VERSION 5.7 ;
  NOWIREEXTENSIONATPIN ON ;
  DIVIDERCHAR "/" ;
  BUSBITCHARS "[]" ;
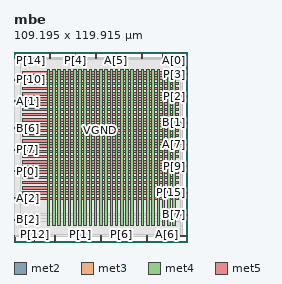
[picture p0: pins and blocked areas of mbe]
MACRO mbe
  CLASS BLOCK ;
  FOREIGN mbe ;
  ORIGIN 0.000 0.000 ;
  SIZE 109.195 BY 119.915 ;
  PIN A[0]
    DIRECTION INPUT ;
    USE SIGNAL ;
    ANTENNAGATEAREA 0.495000 ;
    PORT
      LAYER met2 ;
        RECT 106.350 115.915 106.630 119.915 ;
    END
  END A[0]
  PIN A[1]
    DIRECTION INPUT ;
    USE SIGNAL ;
    ANTENNAGATEAREA 0.196500 ;
    PORT
      LAYER met3 ;
        RECT 0.000 88.440 4.000 89.040 ;
    END
  END A[1]
  PIN A[2]
    DIRECTION INPUT ;
    USE SIGNAL ;
    ANTENNAGATEAREA 0.247500 ;
    PORT
      LAYER met3 ;
        RECT 0.000 27.240 4.000 27.840 ;
    END
  END A[2]
  PIN A[3]
    DIRECTION INPUT ;
    USE SIGNAL ;
    ANTENNAGATEAREA 0.213000 ;
    PORT
      LAYER met2 ;
        RECT 54.830 0.000 55.110 4.000 ;
    END
  END A[3]
  PIN A[4]
    DIRECTION INPUT ;
    USE SIGNAL ;
    ANTENNAGATEAREA 0.126000 ;
    PORT
      LAYER met2 ;
        RECT 22.630 115.915 22.910 119.915 ;
    END
  END A[4]
  PIN A[5]
    DIRECTION INPUT ;
    USE SIGNAL ;
    ANTENNAGATEAREA 0.196500 ;
    PORT
      LAYER met2 ;
        RECT 64.490 115.915 64.770 119.915 ;
    END
  END A[5]
  PIN A[6]
    DIRECTION INPUT ;
    USE SIGNAL ;
    ANTENNAGATEAREA 0.213000 ;
    PORT
      LAYER met2 ;
        RECT 96.690 0.000 96.970 4.000 ;
    END
  END A[6]
  PIN A[7]
    DIRECTION INPUT ;
    USE SIGNAL ;
    ANTENNAGATEAREA 0.159000 ;
    PORT
      LAYER met3 ;
        RECT 105.195 61.240 109.195 61.840 ;
    END
  END A[7]
  PIN B[0]
    DIRECTION INPUT ;
    USE SIGNAL ;
    ANTENNAGATEAREA 0.196500 ;
    PORT
      LAYER met2 ;
        RECT 83.810 0.000 84.090 4.000 ;
    END
  END B[0]
  PIN B[1]
    DIRECTION INPUT ;
    USE SIGNAL ;
    ANTENNAGATEAREA 0.213000 ;
    PORT
      LAYER met3 ;
        RECT 105.195 74.840 109.195 75.440 ;
    END
  END B[1]
  PIN B[2]
    DIRECTION INPUT ;
    USE SIGNAL ;
    ANTENNAGATEAREA 0.159000 ;
    PORT
      LAYER met3 ;
        RECT 0.000 13.640 4.000 14.240 ;
    END
  END B[2]
  PIN B[3]
    DIRECTION INPUT ;
    USE SIGNAL ;
    ANTENNAGATEAREA 0.159000 ;
    PORT
      LAYER met2 ;
        RECT 0.090 0.000 0.370 4.000 ;
    END
  END B[3]
  PIN B[4]
    DIRECTION INPUT ;
    USE SIGNAL ;
    ANTENNAGATEAREA 0.196500 ;
    PORT
      LAYER met2 ;
        RECT 80.590 115.915 80.870 119.915 ;
    END
  END B[4]
  PIN B[5]
    DIRECTION INPUT ;
    USE SIGNAL ;
    ANTENNAGATEAREA 0.159000 ;
    PORT
      LAYER met2 ;
        RECT 93.470 115.915 93.750 119.915 ;
    END
  END B[5]
  PIN B[6]
    DIRECTION INPUT ;
    USE SIGNAL ;
    ANTENNAGATEAREA 0.213000 ;
    PORT
      LAYER met3 ;
        RECT 0.000 71.440 4.000 72.040 ;
    END
  END B[6]
  PIN B[7]
    DIRECTION INPUT ;
    USE SIGNAL ;
    ANTENNAGATEAREA 0.196500 ;
    PORT
      LAYER met3 ;
        RECT 105.195 17.040 109.195 17.640 ;
    END
  END B[7]
  PIN P[0]
    DIRECTION OUTPUT TRISTATE ;
    USE SIGNAL ;
    ANTENNADIFFAREA 0.795200 ;
    PORT
      LAYER met3 ;
        RECT 0.000 44.240 4.000 44.840 ;
    END
  END P[0]
  PIN P[10]
    DIRECTION OUTPUT TRISTATE ;
    USE SIGNAL ;
    ANTENNADIFFAREA 0.795200 ;
    PORT
      LAYER met3 ;
        RECT 0.000 102.040 4.000 102.640 ;
    END
  END P[10]
  PIN P[11]
    DIRECTION OUTPUT TRISTATE ;
    USE SIGNAL ;
    ANTENNADIFFAREA 0.795200 ;
    PORT
      LAYER met3 ;
        RECT 105.195 3.440 109.195 4.040 ;
    END
  END P[11]
  PIN P[12]
    DIRECTION OUTPUT TRISTATE ;
    USE SIGNAL ;
    ANTENNADIFFAREA 0.795200 ;
    PORT
      LAYER met2 ;
        RECT 12.970 0.000 13.250 4.000 ;
    END
  END P[12]
  PIN P[13]
    DIRECTION OUTPUT TRISTATE ;
    USE SIGNAL ;
    ANTENNADIFFAREA 0.795200 ;
    PORT
      LAYER met2 ;
        RECT 25.850 0.000 26.130 4.000 ;
    END
  END P[13]
  PIN P[14]
    DIRECTION OUTPUT TRISTATE ;
    USE SIGNAL ;
    ANTENNADIFFAREA 0.445500 ;
    PORT
      LAYER met2 ;
        RECT 9.750 115.915 10.030 119.915 ;
    END
  END P[14]
  PIN P[15]
    DIRECTION OUTPUT TRISTATE ;
    USE SIGNAL ;
    ANTENNADIFFAREA 0.891000 ;
    PORT
      LAYER met3 ;
        RECT 105.195 30.640 109.195 31.240 ;
    END
  END P[15]
  PIN P[1]
    DIRECTION OUTPUT TRISTATE ;
    USE SIGNAL ;
    ANTENNADIFFAREA 0.795200 ;
    PORT
      LAYER met2 ;
        RECT 41.950 0.000 42.230 4.000 ;
    END
  END P[1]
  PIN P[2]
    DIRECTION OUTPUT TRISTATE ;
    USE SIGNAL ;
    ANTENNADIFFAREA 0.445500 ;
    PORT
      LAYER met3 ;
        RECT 105.195 91.840 109.195 92.440 ;
    END
  END P[2]
  PIN P[3]
    DIRECTION OUTPUT TRISTATE ;
    USE SIGNAL ;
    ANTENNADIFFAREA 0.445500 ;
    PORT
      LAYER met3 ;
        RECT 105.195 105.440 109.195 106.040 ;
    END
  END P[3]
  PIN P[4]
    DIRECTION OUTPUT TRISTATE ;
    USE SIGNAL ;
    ANTENNADIFFAREA 0.795200 ;
    PORT
      LAYER met2 ;
        RECT 38.730 115.915 39.010 119.915 ;
    END
  END P[4]
  PIN P[5]
    DIRECTION OUTPUT TRISTATE ;
    USE SIGNAL ;
    ANTENNADIFFAREA 0.445500 ;
    PORT
      LAYER met2 ;
        RECT 51.610 115.915 51.890 119.915 ;
    END
  END P[5]
  PIN P[6]
    DIRECTION OUTPUT TRISTATE ;
    USE SIGNAL ;
    ANTENNADIFFAREA 0.795200 ;
    PORT
      LAYER met2 ;
        RECT 67.710 0.000 67.990 4.000 ;
    END
  END P[6]
  PIN P[7]
    DIRECTION OUTPUT TRISTATE ;
    USE SIGNAL ;
    ANTENNADIFFAREA 0.795200 ;
    PORT
      LAYER met3 ;
        RECT 0.000 57.840 4.000 58.440 ;
    END
  END P[7]
  PIN P[8]
    DIRECTION OUTPUT TRISTATE ;
    USE SIGNAL ;
    ANTENNADIFFAREA 0.795200 ;
    PORT
      LAYER met3 ;
        RECT 0.000 115.640 4.000 116.240 ;
    END
  END P[8]
  PIN P[9]
    DIRECTION OUTPUT TRISTATE ;
    USE SIGNAL ;
    ANTENNADIFFAREA 0.795200 ;
    PORT
      LAYER met3 ;
        RECT 105.195 47.640 109.195 48.240 ;
    END
  END P[9]
  PIN VGND
    DIRECTION INOUT ;
    USE GROUND ;
    PORT
      LAYER met4 ;
        RECT 24.340 10.640 25.940 109.040 ;
    END
    PORT
      LAYER met4 ;
        RECT 30.940 10.640 32.540 109.040 ;
    END
    PORT
      LAYER met4 ;
        RECT 37.540 10.640 39.140 109.040 ;
    END
    PORT
      LAYER met4 ;
        RECT 44.140 10.640 45.740 109.040 ;
    END
    PORT
      LAYER met4 ;
        RECT 50.740 10.640 52.340 109.040 ;
    END
    PORT
      LAYER met4 ;
        RECT 57.340 10.640 58.940 109.040 ;
    END
    PORT
      LAYER met4 ;
        RECT 63.940 10.640 65.540 109.040 ;
    END
    PORT
      LAYER met4 ;
        RECT 70.540 10.640 72.140 109.040 ;
    END
    PORT
      LAYER met4 ;
        RECT 77.140 10.640 78.740 109.040 ;
    END
    PORT
      LAYER met4 ;
        RECT 83.740 10.640 85.340 109.040 ;
    END
    PORT
      LAYER met4 ;
        RECT 90.340 10.640 91.940 109.040 ;
    END
    PORT
      LAYER met4 ;
        RECT 96.940 10.640 98.540 109.040 ;
    END
    PORT
      LAYER met5 ;
        RECT 5.280 30.030 103.740 31.630 ;
    END
    PORT
      LAYER met5 ;
        RECT 5.280 36.630 103.740 38.230 ;
    END
    PORT
      LAYER met5 ;
        RECT 5.280 43.230 103.740 44.830 ;
    END
    PORT
      LAYER met5 ;
        RECT 5.280 49.830 103.740 51.430 ;
    END
    PORT
      LAYER met5 ;
        RECT 5.280 56.430 103.740 58.030 ;
    END
    PORT
      LAYER met5 ;
        RECT 5.280 63.030 103.740 64.630 ;
    END
    PORT
      LAYER met5 ;
        RECT 5.280 69.630 103.740 71.230 ;
    END
    PORT
      LAYER met5 ;
        RECT 5.280 76.230 103.740 77.830 ;
    END
    PORT
      LAYER met5 ;
        RECT 5.280 82.830 103.740 84.430 ;
    END
    PORT
      LAYER met5 ;
        RECT 5.280 89.430 103.740 91.030 ;
    END
    PORT
      LAYER met5 ;
        RECT 5.280 96.030 103.740 97.630 ;
    END
    PORT
      LAYER met5 ;
        RECT 5.280 102.630 103.740 104.230 ;
    END
  END VGND
  PIN VPWR
    DIRECTION INOUT ;
    USE POWER ;
    PORT
      LAYER met4 ;
        RECT 21.040 10.640 22.640 109.040 ;
    END
    PORT
      LAYER met4 ;
        RECT 27.640 10.640 29.240 109.040 ;
    END
    PORT
      LAYER met4 ;
        RECT 34.240 10.640 35.840 109.040 ;
    END
    PORT
      LAYER met4 ;
        RECT 40.840 10.640 42.440 109.040 ;
    END
    PORT
      LAYER met4 ;
        RECT 47.440 10.640 49.040 109.040 ;
    END
    PORT
      LAYER met4 ;
        RECT 54.040 10.640 55.640 109.040 ;
    END
    PORT
      LAYER met4 ;
        RECT 60.640 10.640 62.240 109.040 ;
    END
    PORT
      LAYER met4 ;
        RECT 67.240 10.640 68.840 109.040 ;
    END
    PORT
      LAYER met4 ;
        RECT 73.840 10.640 75.440 109.040 ;
    END
    PORT
      LAYER met4 ;
        RECT 80.440 10.640 82.040 109.040 ;
    END
    PORT
      LAYER met4 ;
        RECT 87.040 10.640 88.640 109.040 ;
    END
    PORT
      LAYER met4 ;
        RECT 93.640 10.640 95.240 109.040 ;
    END
    PORT
      LAYER met4 ;
        RECT 100.240 10.640 101.840 109.040 ;
    END
    PORT
      LAYER met5 ;
        RECT 5.280 26.730 103.740 28.330 ;
    END
    PORT
      LAYER met5 ;
        RECT 5.280 33.330 103.740 34.930 ;
    END
    PORT
      LAYER met5 ;
        RECT 5.280 39.930 103.740 41.530 ;
    END
    PORT
      LAYER met5 ;
        RECT 5.280 46.530 103.740 48.130 ;
    END
    PORT
      LAYER met5 ;
        RECT 5.280 53.130 103.740 54.730 ;
    END
    PORT
      LAYER met5 ;
        RECT 5.280 59.730 103.740 61.330 ;
    END
    PORT
      LAYER met5 ;
        RECT 5.280 66.330 103.740 67.930 ;
    END
    PORT
      LAYER met5 ;
        RECT 5.280 72.930 103.740 74.530 ;
    END
    PORT
      LAYER met5 ;
        RECT 5.280 79.530 103.740 81.130 ;
    END
    PORT
      LAYER met5 ;
        RECT 5.280 86.130 103.740 87.730 ;
    END
    PORT
      LAYER met5 ;
        RECT 5.280 92.730 103.740 94.330 ;
    END
    PORT
      LAYER met5 ;
        RECT 5.280 99.330 103.740 100.930 ;
    END
    PORT
      LAYER met5 ;
        RECT 5.280 105.930 103.740 107.530 ;
    END
  END VPWR
  OBS
      LAYER li1 ;
        RECT 5.520 10.795 103.500 108.885 ;
      LAYER met1 ;
        RECT 0.070 10.640 106.650 109.040 ;
      LAYER met2 ;
        RECT 0.100 115.635 9.470 116.690 ;
        RECT 10.310 115.635 22.350 116.690 ;
        RECT 23.190 115.635 38.450 116.690 ;
        RECT 39.290 115.635 51.330 116.690 ;
        RECT 52.170 115.635 64.210 116.690 ;
        RECT 65.050 115.635 80.310 116.690 ;
        RECT 81.150 115.635 93.190 116.690 ;
        RECT 94.030 115.635 106.070 116.690 ;
        RECT 0.100 4.280 106.620 115.635 ;
        RECT 0.650 3.555 12.690 4.280 ;
        RECT 13.530 3.555 25.570 4.280 ;
        RECT 26.410 3.555 41.670 4.280 ;
        RECT 42.510 3.555 54.550 4.280 ;
        RECT 55.390 3.555 67.430 4.280 ;
        RECT 68.270 3.555 83.530 4.280 ;
        RECT 84.370 3.555 96.410 4.280 ;
        RECT 97.250 3.555 106.620 4.280 ;
      LAYER met3 ;
        RECT 4.400 115.240 105.195 116.105 ;
        RECT 3.990 106.440 105.195 115.240 ;
        RECT 3.990 105.040 104.795 106.440 ;
        RECT 3.990 103.040 105.195 105.040 ;
        RECT 4.400 101.640 105.195 103.040 ;
        RECT 3.990 92.840 105.195 101.640 ;
        RECT 3.990 91.440 104.795 92.840 ;
        RECT 3.990 89.440 105.195 91.440 ;
        RECT 4.400 88.040 105.195 89.440 ;
        RECT 3.990 75.840 105.195 88.040 ;
        RECT 3.990 74.440 104.795 75.840 ;
        RECT 3.990 72.440 105.195 74.440 ;
        RECT 4.400 71.040 105.195 72.440 ;
        RECT 3.990 62.240 105.195 71.040 ;
        RECT 3.990 60.840 104.795 62.240 ;
        RECT 3.990 58.840 105.195 60.840 ;
        RECT 4.400 57.440 105.195 58.840 ;
        RECT 3.990 48.640 105.195 57.440 ;
        RECT 3.990 47.240 104.795 48.640 ;
        RECT 3.990 45.240 105.195 47.240 ;
        RECT 4.400 43.840 105.195 45.240 ;
        RECT 3.990 31.640 105.195 43.840 ;
        RECT 3.990 30.240 104.795 31.640 ;
        RECT 3.990 28.240 105.195 30.240 ;
        RECT 4.400 26.840 105.195 28.240 ;
        RECT 3.990 18.040 105.195 26.840 ;
        RECT 3.990 16.640 104.795 18.040 ;
        RECT 3.990 14.640 105.195 16.640 ;
        RECT 4.400 13.240 105.195 14.640 ;
        RECT 3.990 4.440 105.195 13.240 ;
        RECT 3.990 3.575 104.795 4.440 ;
      LAYER met4 ;
        RECT 49.975 49.815 50.340 72.585 ;
        RECT 52.740 49.815 53.640 72.585 ;
        RECT 56.040 49.815 56.940 72.585 ;
        RECT 59.340 49.815 60.240 72.585 ;
        RECT 62.640 49.815 63.540 72.585 ;
        RECT 65.940 49.815 66.840 72.585 ;
        RECT 69.240 49.815 70.140 72.585 ;
        RECT 72.540 49.815 73.440 72.585 ;
        RECT 75.840 49.815 76.740 72.585 ;
        RECT 79.140 49.815 79.745 72.585 ;
  END
END mbe
END LIBRARY

